One B-rep face of a CAD part: STEP entity #662.
In plain terms, the planar face has unit normal (0, -1, 0).
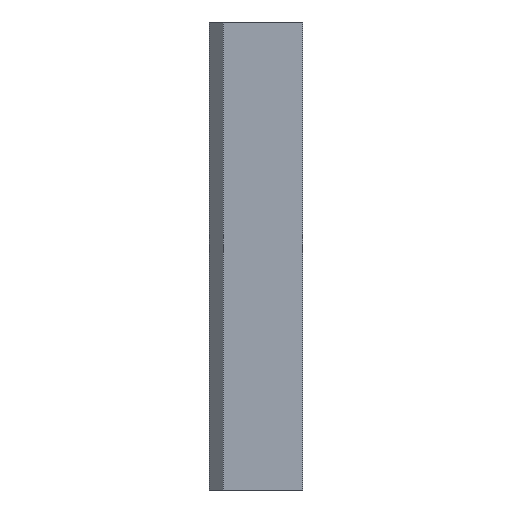
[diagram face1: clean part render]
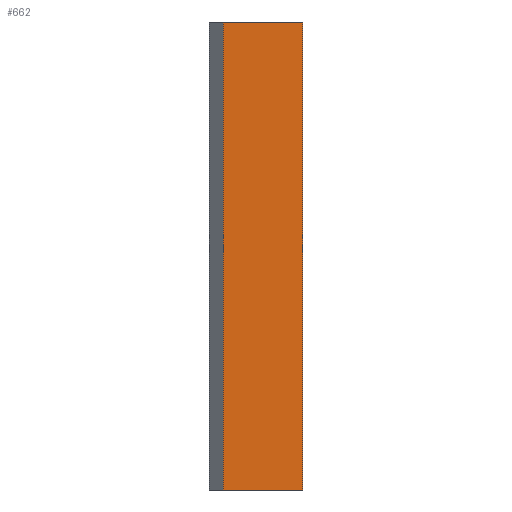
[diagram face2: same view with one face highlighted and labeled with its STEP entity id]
Its self-contained STEP definition (entity closure, numbers rounded to 3 decimals):
#286=CARTESIAN_POINT('Vertex',(20.,0.,-50.)) ;
#289=CARTESIAN_POINT('Line Origine',(11.5,0.,-50.)) ;
#293=CARTESIAN_POINT('Vertex',(3.,0.,-50.)) ;
#316=CARTESIAN_POINT('Line Origine',(3.,0.,0.)) ;
#320=CARTESIAN_POINT('Vertex',(3.,0.,50.)) ;
#340=CARTESIAN_POINT('Line Origine',(11.5,0.,50.)) ;
#344=CARTESIAN_POINT('Vertex',(20.,0.,50.)) ;
#571=CARTESIAN_POINT('Line Origine',(20.,0.,0.)) ;
#651=CARTESIAN_POINT('Axis2P3D Location',(3.,0.,50.)) ;
#290=DIRECTION('Vector Direction',(1.,0.,0.)) ;
#317=DIRECTION('Vector Direction',(0.,0.,-1.)) ;
#341=DIRECTION('Vector Direction',(1.,0.,0.)) ;
#572=DIRECTION('Vector Direction',(0.,0.,-1.)) ;
#652=DIRECTION('Axis2P3D Direction',(0.,1.,0.)) ;
#653=DIRECTION('Axis2P3D XDirection',(0.,-0.,1.)) ;
#654=AXIS2_PLACEMENT_3D('Plane Axis2P3D',#651,#652,#653) ;
#657=ORIENTED_EDGE('',*,*,#295,.T.) ;
#658=ORIENTED_EDGE('',*,*,#575,.F.) ;
#659=ORIENTED_EDGE('',*,*,#346,.F.) ;
#660=ORIENTED_EDGE('',*,*,#322,.T.) ;
#291=VECTOR('Line Direction',#290,1.) ;
#318=VECTOR('Line Direction',#317,1.) ;
#342=VECTOR('Line Direction',#341,1.) ;
#573=VECTOR('Line Direction',#572,1.) ;
#662=ADVANCED_FACE('A915-100X200',(#661),#655,.F.) ;
#295=EDGE_CURVE('',#294,#287,#292,.T.) ;
#322=EDGE_CURVE('',#321,#294,#319,.T.) ;
#346=EDGE_CURVE('',#321,#345,#343,.T.) ;
#575=EDGE_CURVE('',#345,#287,#574,.T.) ;
#656=EDGE_LOOP('',(#657,#658,#659,#660)) ;
#661=FACE_OUTER_BOUND('',#656,.T.) ;
#292=LINE('Line',#289,#291) ;
#319=LINE('Line',#316,#318) ;
#343=LINE('Line',#340,#342) ;
#574=LINE('Line',#571,#573) ;
#655=PLANE('Plane',#654) ;
#287=VERTEX_POINT('',#286) ;
#294=VERTEX_POINT('',#293) ;
#321=VERTEX_POINT('',#320) ;
#345=VERTEX_POINT('',#344) ;
